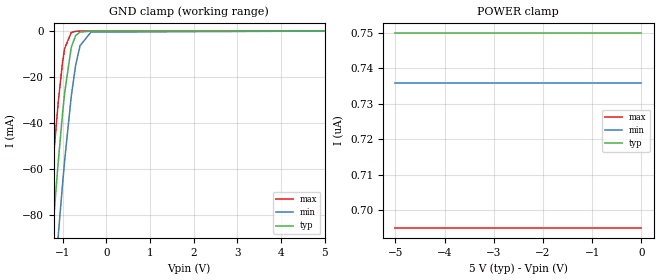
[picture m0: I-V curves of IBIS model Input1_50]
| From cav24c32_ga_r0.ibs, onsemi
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|//////////////////////////////////////////////////////////////////////////////
|//////////////////////////////////////////////////////////////////////////////
[Model]  Input1_50
Model_type Input
Vinh = 3.50
Vinl = 1.50
|  variable   typ   min   max
C_comp   6pF   6pF   6pF
|//////////////////////////////////////////////////////////////////////////////
[Temperature Range]   25   125   -40
|//////////////////////////////////////////////////////////////////////////////
[Voltage Range]   5.00V   4.50V   5.50V
|//////////////////////////////////////////////////////////////////////////////
[POWER Clamp Reference] 5.00V   4.50V   5.50V
|//////////////////////////////////////////////////////////////////////////////
[GND Clamp Reference]   0V   0V   0V
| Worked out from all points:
|   GND clamp passes 1 mA (typ) near -0.65 V on its own axis
|//////////////////////////////////////////////////////////////////////////////
[GND Clamp]
|   Voltage   I(typ)   I(min)   I(max)
-5V       -1.18A     -1.2A      -1.16A
-1.4V     -132mA     -164mA     -104mA
-1.3V     -106mA     -138mA     -77.6mA
-1.2V     -80.6mA    -113mA     -53.1mA
-1.1V     -57.1mA    -89mA      -31.1mA
-1V       -35.8mA    -66.4mA    -13.5mA
-950mV    -26.5mA    -55.8mA    -7.44mA
-800mV    -7mA       -28.2mA    -607uA
-700mV    -1.93mA    -14.8mA    -100uA
-600mV    -447uA     -6.36mA    -26.2uA
-350mV    -15.5uA    -430uA     -8.19uA
5V        750nA      736nA      695nA
|//////////////////////////////////////////////////////////////////////////////
[POWER Clamp]
|   Voltage   I(typ)   I(min)   I(max)
-5V       750nA      736nA      695nA
-4.5V     750nA      736nA      695nA
-4V       750nA      736nA      695nA
-3.5V     750nA      736nA      695nA
-3V       750nA      736nA      695nA
-2.5V     750nA      736nA      695nA
-2V       750nA      736nA      695nA
-1.5V     750nA      736nA      695nA
-1V       750nA      736nA      695nA
-500mV    750nA      736nA      695nA
0V        750nA      736nA      695nA
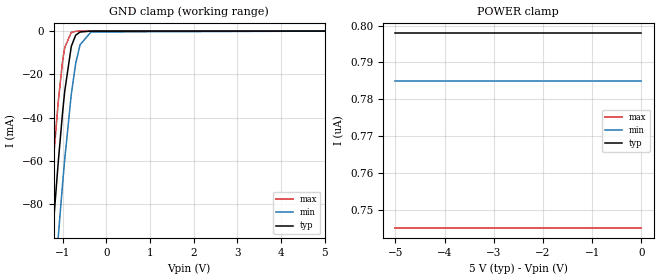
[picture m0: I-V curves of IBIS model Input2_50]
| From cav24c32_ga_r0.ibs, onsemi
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|//////////////////////////////////////////////////////////////////////////////
|//////////////////////////////////////////////////////////////////////////////
[Model]  Input2_50
Model_type Input
Vinh = 3.50
Vinl = 1.50
|  variable   typ   min   max
C_comp   6pF   6pF   6pF
|//////////////////////////////////////////////////////////////////////////////
[Temperature Range]   25   125   -40
|//////////////////////////////////////////////////////////////////////////////
[Voltage Range]   5.00V   4.50V   5.50V
|//////////////////////////////////////////////////////////////////////////////
[POWER Clamp Reference] 5.00V   4.50V   5.50V
|//////////////////////////////////////////////////////////////////////////////
[GND Clamp Reference]   0V   0V   0V
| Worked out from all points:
|   GND clamp passes 1 mA (typ) near -0.65 V on its own axis
|//////////////////////////////////////////////////////////////////////////////
[GND Clamp]
|   Voltage   I(typ)   I(min)   I(max)
-5V       -1.3A      -1.32A     -1.27A
-1.4V     -143mA     -177mA     -112mA
-1.3V     -114mA     -149mA     -84mA
-1.2V     -86.6mA    -122mA     -57.1mA
-1.1V     -60.8mA    -95.3mA    -32.9mA
-1V       -37.7mA    -70.6mA    -13.9mA
-950mV    -27.7mA    -59.1mA    -7.55mA
-800mV    -7.04mA    -29.2mA    -595uA
-700mV    -1.9mA     -15mA      -99.1uA
-600mV    -437uA     -6.34mA    -26.6uA
-350mV    -15.9uA    -421uA     -8.87uA
5V        798nA      785nA      745nA
|//////////////////////////////////////////////////////////////////////////////
[POWER Clamp]
|   Voltage   I(typ)   I(min)   I(max)
-5V       798nA      785nA      745nA
-4.5V     798nA      785nA      745nA
-4V       798nA      785nA      745nA
-3.5V     798nA      785nA      745nA
-3V       798nA      785nA      745nA
-2.5V     798nA      785nA      745nA
-2V       798nA      785nA      745nA
-1.5V     798nA      785nA      745nA
-1V       798nA      785nA      745nA
-500mV    798nA      785nA      745nA
0V        798nA      785nA      745nA
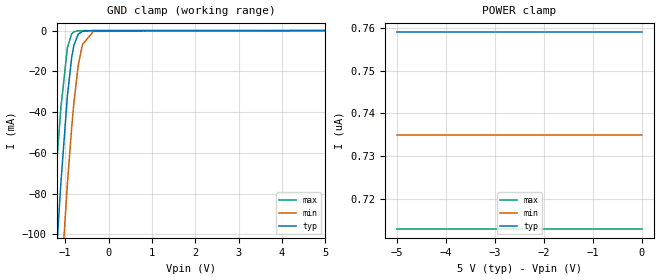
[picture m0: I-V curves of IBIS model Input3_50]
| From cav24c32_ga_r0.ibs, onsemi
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|//////////////////////////////////////////////////////////////////////////////
|//////////////////////////////////////////////////////////////////////////////
[Model]  Input3_50
Model_type Input
Vinh = 3.50
Vinl = 1.50
|  variable   typ   min   max
C_comp   6pF   6pF   6pF
|//////////////////////////////////////////////////////////////////////////////
[Temperature Range]   25   125   -40
|//////////////////////////////////////////////////////////////////////////////
[Voltage Range]   5.00V   4.50V   5.50V
|//////////////////////////////////////////////////////////////////////////////
[POWER Clamp Reference] 5.00V   4.50V   5.50V
|//////////////////////////////////////////////////////////////////////////////
[GND Clamp Reference]   0V   0V   0V
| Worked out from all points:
|   GND clamp passes 1 mA (typ) near -0.66 V on its own axis
|//////////////////////////////////////////////////////////////////////////////
[GND Clamp]
|   Voltage   I(typ)   I(min)   I(max)
-5V       -1.69A     -1.8A      -1.46A
-1.4V     -182mA     -237mA     -130mA
-1.3V     -144mA     -198mA     -97.1mA
-1.2V     -109mA     -161mA     -66.1mA
-1.1V     -75mA      -125mA     -38.1mA
-950mV    -32.3mA    -75.5mA    -8.51mA
-850mV    -13.1mA    -47.5mA    -1.58mA
-800mV    -7.25mA    -35.6mA    -604uA
-700mV    -1.77mA    -17.2mA    -94.4uA
-600mV    -376uA     -6.77mA    -25.8uA
-350mV    -12.4uA    -383uA     -9.33uA
5V        759nA      735nA      713nA
|//////////////////////////////////////////////////////////////////////////////
[POWER Clamp]
|   Voltage   I(typ)   I(min)   I(max)
-5V       759nA      735nA      713nA
-4.5V     759nA      735nA      713nA
-4V       759nA      735nA      713nA
-3.5V     759nA      735nA      713nA
-3V       759nA      735nA      713nA
-2.5V     759nA      735nA      713nA
-2V       759nA      735nA      713nA
-1.5V     759nA      735nA      713nA
-1V       759nA      735nA      713nA
-500mV    759nA      735nA      713nA
0V        759nA      735nA      713nA
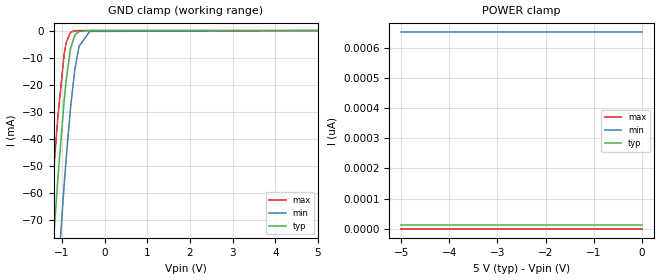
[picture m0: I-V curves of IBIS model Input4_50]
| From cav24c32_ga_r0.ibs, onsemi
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|//////////////////////////////////////////////////////////////////////////////
|//////////////////////////////////////////////////////////////////////////////
[Model]  Input4_50
Model_type Input
Vinh = 3.50
Vinl = 1.50
|  variable   typ   min   max
C_comp   6pF   6pF   6pF
|//////////////////////////////////////////////////////////////////////////////
[Temperature Range]   25   125   -40
|//////////////////////////////////////////////////////////////////////////////
[Voltage Range]   5.00V   4.50V   5.50V
|//////////////////////////////////////////////////////////////////////////////
[POWER Clamp Reference] 5.00V   4.50V   5.50V
|//////////////////////////////////////////////////////////////////////////////
[GND Clamp Reference]   0V   0V   0V
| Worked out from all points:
|   GND clamp passes 1 mA (typ) near -0.66 V on its own axis
|//////////////////////////////////////////////////////////////////////////////
[GND Clamp]
|   Voltage   I(typ)   I(min)   I(max)
-5V       -1.09A     -1.2A      -1.02A
-1.4V     -125mA     -167mA     -98mA
-1.3V     -101mA     -141mA     -74.9mA
-1.2V     -77.3mA    -115mA     -52.7mA
-1.1V     -55.1mA    -90.9mA    -32.3mA
-950mV    -25.8mA    -56.9mA    -8.67mA
-900mV    -17.9mA    -46.6mA    -4.22mA
-800mV    -6.59mA    -28.3mA    -650uA
-700mV    -1.64mA    -14.3mA    -78.2uA
-600mV    -327uA     -5.78mA    -9.04uA
-350mV    -4.84uA    -303uA     -40.4nA
5V        12pA       651pA      26.4fA
|//////////////////////////////////////////////////////////////////////////////
[POWER Clamp]
|   Voltage   I(typ)   I(min)   I(max)
-5V       12pA       651pA      26.2fA
-4.5V     12pA       651pA      26.2fA
-4V       12pA       651pA      26.2fA
-3.5V     12pA       651pA      26.2fA
-3V       12pA       651pA      26.2fA
-2.5V     12pA       651pA      26.2fA
-2V       12pA       651pA      26.2fA
-1.5V     12pA       651pA      26.2fA
-1V       12pA       651pA      26.2fA
-500mV    12pA       651pA      26.2fA
0V        12pA       651pA      26.2fA
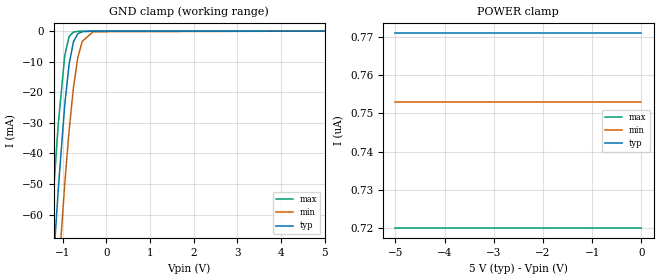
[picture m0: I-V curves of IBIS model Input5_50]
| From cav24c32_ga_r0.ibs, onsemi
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|//////////////////////////////////////////////////////////////////////////////
|//////////////////////////////////////////////////////////////////////////////
[Model]  Input5_50
Model_type Input
Vinh = 3.50
Vinl = 1.50
|  variable   typ   min   max
C_comp   6pF   6pF   6pF
|//////////////////////////////////////////////////////////////////////////////
[Temperature Range]   25   125   -40
|//////////////////////////////////////////////////////////////////////////////
[Voltage Range]   5.00V   4.50V   5.50V
|//////////////////////////////////////////////////////////////////////////////
[POWER Clamp Reference] 5.00V   4.50V   5.50V
|//////////////////////////////////////////////////////////////////////////////
[GND Clamp Reference]   0V   0V   0V
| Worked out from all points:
|   GND clamp passes 1 mA (typ) near -0.66 V on its own axis
|//////////////////////////////////////////////////////////////////////////////
[GND Clamp]
|   Voltage   I(typ)   I(min)   I(max)
-5V       -1.08A     -1.1A      -1.07A
-1.4V     -121mA     -149mA     -98mA
-1.3V     -96.7mA    -126mA     -74.1mA
-1.2V     -73.7mA    -103mA     -51.3mA
-1.1V     -52.1mA    -80.5mA    -30.7mA
-950mV    -24.1mA    -50mA      -7.96mA
-850mV    -10.8mA    -32.5mA    -1.75mA
-750mV    -3.45mA    -18.4mA    -314uA
-650mV    -870uA     -8.62mA    -86.5uA
-550mV    -216uA     -3.36mA    -48uA
-300mV    -22.1uA    -214uA     -23.3uA
5V        771nA      753nA      720nA
|//////////////////////////////////////////////////////////////////////////////
[POWER Clamp]
|   Voltage   I(typ)   I(min)   I(max)
-5V       771nA      753nA      720nA
-4.5V     771nA      753nA      720nA
-4V       771nA      753nA      720nA
-3.5V     771nA      753nA      720nA
-3V       771nA      753nA      720nA
-2.5V     771nA      753nA      720nA
-2V       771nA      753nA      720nA
-1.5V     771nA      753nA      720nA
-1V       771nA      753nA      720nA
-500mV    771nA      753nA      720nA
0V        771nA      753nA      720nA
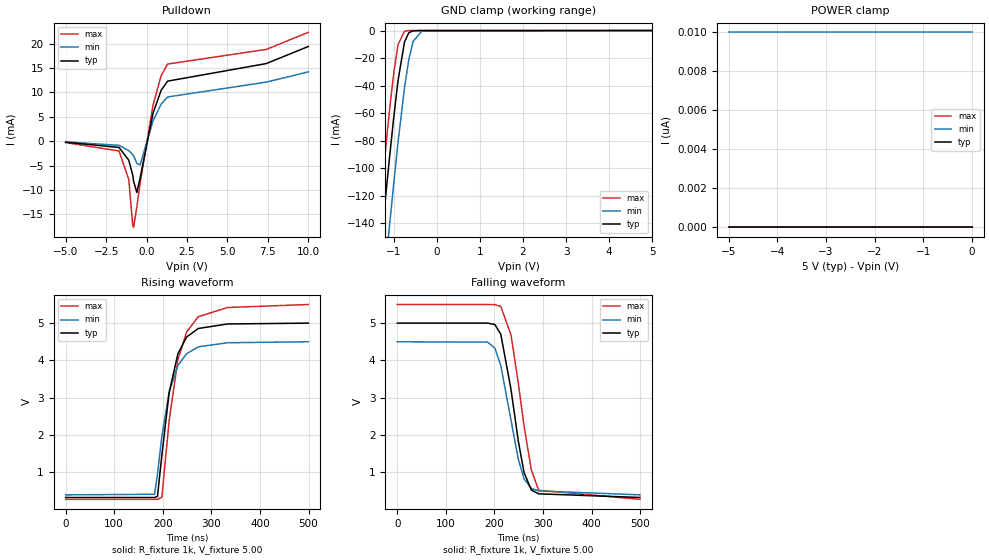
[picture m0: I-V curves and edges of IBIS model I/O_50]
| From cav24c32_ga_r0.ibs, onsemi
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|//////////////////////////////////////////////////////////////////////////////
|//////////////////////////////////////////////////////////////////////////////
[Model] I/O_50
Model_type I/O_open_drain
Vinh = 3.50
Vinl = 1.50
Vmeas = 2.50
Vref = 5.00
Rref = 1000
Cref = 0pF
|  variable   typ   min   max
C_comp   8pF   8pF   8pF
|//////////////////////////////////////////////////////////////////////////////
[Temperature Range]   25   125   -40
|//////////////////////////////////////////////////////////////////////////////
[Voltage Range]   5.00V   4.50V   5.50V
|//////////////////////////////////////////////////////////////////////////////
[Pulldown Reference]   0V   0V   0V
|//////////////////////////////////////////////////////////////////////////////
[POWER Clamp Reference] 5.00V   4.50V   5.50V
|//////////////////////////////////////////////////////////////////////////////
[GND Clamp Reference]   0V   0V   0V
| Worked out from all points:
|   slope of the pulldown table from 0 to 0.75 V, typ, clamps not added: 81.3 ohm
|   GND clamp passes 1 mA (typ) near -0.62 V on its own axis
|   falling waveform, R_fixture 1k, V_fixture 5.00: 20-80 % time 32.5ns typ, 35.3ns min, 34.9ns max; typ from 5 V to 0.32 V
|   rising waveform, R_fixture 1k, V_fixture 5.00: 20-80 % time 31.6ns typ, 33.5ns min, 34.4ns max; typ from 0.32 V to 5 V
|//////////////////////////////////////////////////////////////////////////////
[Pulldown]
|   Voltage   I(typ)   I(min)   I(max)
-5V       -202uA     -141uA     -288uA
-1.7V     -1.28mA    -845uA     -2mA
-1.1V     -3.88mA    -1.95mA    -7.84mA
-850mV    -7mA       -2.77mA    -17.3mA
-800mV    -8.23mA    -3.01mA    -17.6mA
-600mV    -10.5mA    -4.51mA    -13.4mA
-400mV    -7.57mA    -4.87mA    -8.69mA
400mV     5.71mA     4.16mA     7.37mA
900mV     10.4mA     7.6mA      13.4mA
1.3V      12.3mA     9.06mA     15.8mA
7.4V      15.9mA     12.1mA     18.8mA
10V       19.4mA     14.2mA     22.3mA
|//////////////////////////////////////////////////////////////////////////////
[GND Clamp]
|   Voltage   I(typ)   I(min)   I(max)
-5V       -1.49A     -1.55A     -1.44A
-1.4V     -190mA     -241mA     -154mA
-1.3V     -157mA     -208mA     -121mA
-1.2V     -124mA     -174mA     -88.8mA
-1.1V     -92.7mA    -142mA     -58.2mA
-1V       -62.9mA    -111mA     -30.7mA
-900mV    -36.1mA    -80.9mA    -10.1mA
-750mV    -8.17mA    -41.3mA    -428uA
-650mV    -1.58mA    -20.9mA    -34.3uA
-550mV    -231uA     -7.87mA    -2.68uA
-350mV    -4.32uA    -527uA     -16.2nA
5V        10pA       9.98nA     8.87fA
|//////////////////////////////////////////////////////////////////////////////
[POWER Clamp]
|   Voltage   I(typ)   I(min)   I(max)
-5V       10pA       9.98nA     8.87fA
-4.5V     10pA       9.98nA     8.87fA
-4V       10pA       9.98nA     8.87fA
-3.5V     10pA       9.98nA     8.87fA
-3V       10pA       9.98nA     8.87fA
-2.5V     10pA       9.98nA     8.87fA
-2V       10pA       9.98nA     8.87fA
-1.5V     10pA       9.98nA     8.87fA
-1V       10pA       9.98nA     8.87fA
-500mV    10pA       9.98nA     8.87fA
0V        10pA       9.98nA     8.87fA
|//////////////////////////////////////////////////////////////////////////////
|//////////////////////////////////////////////////////////////////////////////
[Ramp]
|  variable   typ   min   max
dV/dt_r   2.808E+00/3.300E-08  2.466E+00/3.300E-08  3.138E+00/3.300E-08
dV/dt_f   2.808E+00/3.300E-08  2.466E+00/3.300E-08  3.138E+00/3.300E-08
R_load = 1k
|/////////////////////////////////////////////////////////////////////////////
[Falling Waveform]
R_fixture = 1k
V_fixture = 5.00
V_fixture_min = 4.50
V_fixture_max = 5.50
C_fixture = 0p
|   time   V(typ)   V(min)   V(max)
0s        5V         4.5V       5.5V
186ns     5V         4.49V      5.499V
201ns     4.96V      4.327V     5.496V
213ns     4.702V     3.862V     5.449V
234ns     3.224V     2.398V     4.685V
249ns     1.839V     1.351V     3.396V
261ns     986.3mV    817.4mV    2.233V
276ns     518.5mV    562.5mV    1.055V
291ns     417.6mV    495.7mV    514.1mV
499.5ns   320mV      390mV      270mV
|//////////////////////////////////////////////////////////////////////////////
[Rising Waveform]
R_fixture = 1k
V_fixture = 5.00
V_fixture_min = 4.50
V_fixture_max = 5.50
C_fixture = 0p
|   time   V(typ)   V(min)   V(max)
0s        320mV      390mV      270mV
183ns     320mV      405.4mV    270mV
189ns     348.9mV    944.6mV    270mV
198ns     1.453V     1.963V     324.4mV
213ns     3.134V     3.153V     2.375V
231ns     4.177V     3.863V     4.015V
249ns     4.628V     4.179V     4.763V
273ns     4.856V     4.363V     5.173V
333ns     4.977V     4.473V     5.419V
499.5ns   5V         4.5V       5.5V
